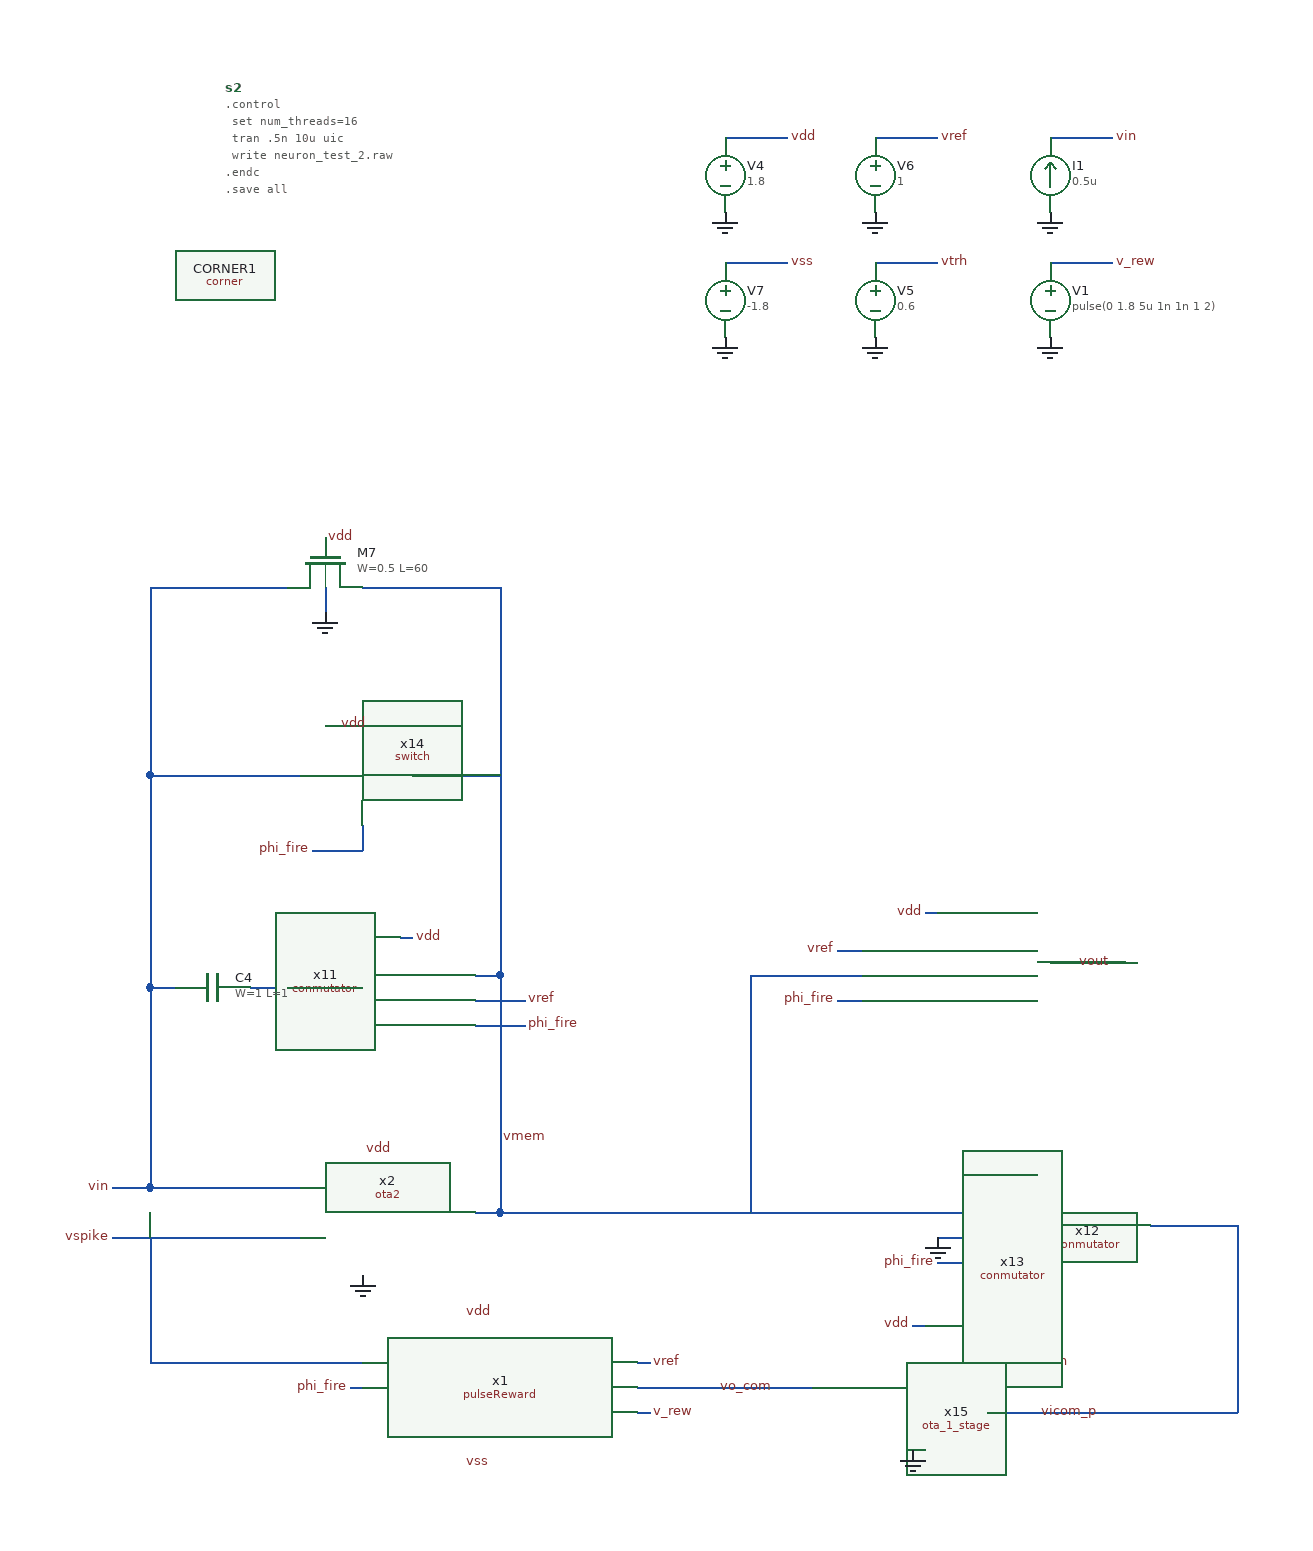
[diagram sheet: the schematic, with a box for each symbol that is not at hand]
v {xschem version=3.4.5 file_version=1.2
}
G {}
K {}
V {}
S {}
E {}
B 2 560 330 1360 730 {flags=graph
y1=0
y2=1.8
ypos1=0
ypos2=2
divy=5
subdivy=1
unity=1
x1=5e-12
x2=1e-05
divx=5
subdivx=1


dataset=-1
unitx=1
logx=0
logy=0
color=12
node=vout
linewidth_mult=5}
B 2 560 -820 1360 -420 {flags=graph

y2=1.8
ypos1=0
ypos2=2
divy=5
subdivy=1
unity=1
x1=5e-12
x2=1e-05
divx=5
subdivx=1


dataset=-1
unitx=1
logx=0
logy=0
color=7
node=vmem
y1=0
linewidth_mult=5}
B 2 560 -1220 1360 -820 {flags=graph
y1=0

ypos1=0
ypos2=2
divy=5
subdivy=1
unity=1
x1=5e-12
x2=1e-05
divx=5
subdivx=1


dataset=-1
unitx=1
logx=0
logy=0
color=4
node=vspike
y2=1.8
linewidth_mult=5}
B 2 560 -70 1360 330 {flags=graph
y1=0
y2=1.8
ypos1=0
ypos2=2
divy=5
subdivy=1
unity=1
x1=5e-12
x2=1e-05
divx=5
subdivx=1


dataset=-1
unitx=1
logx=0
logy=0

color=10
node=vin
linewidth_mult=5}
B 2 -1280 -520 -480 -120 {flags=graph
y1=-0.056
y2=1.5
ypos1=0
ypos2=2
divy=5
subdivy=1
unity=1
x1=5e-12
x2=1e-05
divx=5
subdivx=1


dataset=-1
unitx=1
logx=0
logy=0


color="4 5"
node="vicom_p
vtrh"
linewidth_mult=5}
B 2 -1330 20 -530 420 {flags=graph
y1=4.9e-05
y2=1.9
ypos1=0
ypos2=2
divy=5
subdivy=1
unity=1
x1=5e-12
x2=1e-05
divx=5
subdivx=1


dataset=-1
unitx=1
logx=0
logy=0



color=6
node=vo_com
linewidth_mult=5}
B 2 -1330 420 -530 820 {flags=graph
y1=-0.096
y2=1.9
ypos1=0
ypos2=2
divy=5
subdivy=1
unity=1
x1=5e-12
x2=1e-05
divx=5
subdivx=1


dataset=-1
unitx=1
logx=0
logy=0




color=8
node=phi_fire
linewidth_mult=5}
B 2 -1280 -920 -480 -520 {flags=graph
y1=0
y2=1.8
ypos1=0
ypos2=2
divy=5
subdivy=1
unity=1
x1=5e-12
x2=1e-05
divx=5
subdivx=1


dataset=-1
unitx=1
logx=0
logy=0


color=12
node=v_rew
linewidth_mult=5}
B 2 1360 -820 2160 -420 {flags=graph
y1=0
y2=1.8
ypos1=0
ypos2=2
divy=5
subdivy=1
unity=1
x1=5e-12
x2=1e-05
divx=5
subdivx=1


dataset=-1
unitx=1
logx=0
logy=0
color=12
node=vout
linewidth_mult=5}
B 2 1360 -1220 2160 -820 {flags=graph
y1=0
y2=1.8
ypos1=0
ypos2=2
divy=5
subdivy=1
unity=1
x1=5e-12
x2=1e-05
divx=5
subdivx=1


dataset=-1
unitx=1
logx=0
logy=0

color=10
node=vin
linewidth_mult=5}
B 2 -2130 420 -1330 820 {flags=graph
y1=-0.056
y2=1.5
ypos1=0
ypos2=2
divy=5
subdivy=1
unity=1
x1=5e-12
x2=1e-05
divx=5
subdivx=1


dataset=-1
unitx=1
logx=0
logy=0


color="4 5"
node="vicom_p
vtrh"
linewidth_mult=5}
B 2 -2130 20 -1330 420 {flags=graph
y1=0
y2=1.8
ypos1=0
ypos2=2
divy=5
subdivy=1
unity=1
x1=5e-12
x2=1e-05
divx=5
subdivx=1


dataset=-1
unitx=1
logx=0
logy=0


color=12
node=v_rew
linewidth_mult=5}
N 140 620 170 620 {
lab=vo_com}
N 310 600 350 600 {
lab=vtrh}
N 250 570 260 570 {
lab=vdd}
N 190 310 210 310 {
lab=phi_fire}
N 190 270 210 270 {
lab=vref}
N 360 280 380 280 {
lab=vout}
N -160 260 -150 260 {
lab=vdd}
N -100 310 -60 310 {
lab=vref}
N -100 290 -80 290 {
lab=vmem}
N -100 330 -60 330 {
lab=phi_fire}
N -280 300 -250 300 {
lab=#net1}
N -80 20 -80 290 {
lab=vmem}
N -360 130 -360 300 {
lab=vin}
N -360 300 -340 300 {
lab=vin}
N -360 20 -360 130 {
lab=vin}
N -190 170 -190 190 {
lab=phi_fire}
N -230 190 -190 190 {
lab=phi_fire}
N -80 290 -80 480 {
lab=vmem}
N -360 300 -360 460 {
lab=vin}
N -360 460 -240 460 {
lab=vin}
N -390 460 -360 460 {
lab=vin}
N 100 -380 150 -380 {
lab=vdd}
N 360 -380 410 -380 {
lab=vin}
N 220 -280 270 -280 {
lab=vtrh}
N 220 -380 270 -380 {
lab=vref}
N 310 640 510 640 {
lab=vicom_p}
N 270 500 290 500 {
lab=GND}
N 270 520 290 520 {
lab=phi_fire}
N 270 480 290 480 {
lab=vmem}
N 340 450 350 450 {
lab=vdd}
N 90 480 270 480 {
lab=vmem}
N 440 490 510 490 {
lab=vicom_p}
N 510 490 510 640 {
lab=vicom_p}
N -150 130 -80 130 {
lab=vmem}
N -360 130 -240 130 {
lab=vin}
N -220 90 -210 90 {
lab=vdd}
N 380 280 420 280 {
lab=vout}
N -100 480 -80 480 {
lab=vmem}
N 120 290 120 480 {
lab=vmem}
N 120 290 210 290 {
lab=vmem}
N -80 480 90 480 {
lab=vmem}
N 260 240 270 240 {
lab=vdd}
N 100 -280 150 -280 {
lab=vss}
N 250 670 260 670 {
lab=GND}
N -390 500 -240 500 {
lab=vspike}
N -360 500 -360 600 {
lab=vspike}
N -360 600 -190 600 {
lab=vspike}
N 30 620 140 620 {
lab=vo_com}
N 30 600 40 600 {
lab=vref}
N -200 620 -190 620 {
lab=phi_fire}
N -220 -20 -220 0 {
lab=GND}
N -360 -20 -250 -20 {
lab=vin}
N -360 -20 -360 20 {
lab=vin}
N -190 -20 -80 -20 {
lab=vmem}
N -80 -20 -80 20 {
lab=vmem}
N 360 -280 410 -280 {
lab=v_rew}
N 30 640 40 640 {
lab=v_rew}
C {devices/code_shown.sym} -300 -420 0 0 {name=s2 only_toplevel=false value="
.control
 set num_threads=16
 tran .5n 10u uic
 write neuron_test_2.raw
.endc
.save all" }
C {sky130_fd_pr/corner.sym} -300 -270 0 0 {name=CORNER1 only_toplevel=true corner=tt}
C {devices/lab_wire.sym} -110 560 0 1 {name=p48 sig_type=std_logic lab=vdd}
C {devices/lab_wire.sym} 140 620 0 0 {name=p49 sig_type=std_logic lab=vo_com}
C {devices/lab_wire.sym} 350 600 0 1 {name=p50 sig_type=std_logic lab=vtrh}
C {devices/lab_wire.sym} 250 570 0 0 {name=p51 sig_type=std_logic lab=vdd}
C {devices/lab_wire.sym} -390 500 0 0 {name=p52 sig_type=std_logic lab=vspike}
C {devices/lab_wire.sym} 190 310 0 0 {name=p53 sig_type=std_logic lab=phi_fire}
C {devices/lab_wire.sym} 190 270 0 0 {name=p54 sig_type=std_logic lab=vref}
C {devices/lab_wire.sym} 260 240 0 0 {name=p56 sig_type=std_logic lab=vdd}
C {devices/lab_wire.sym} -150 260 0 1 {name=p57 sig_type=std_logic lab=vdd}
C {devices/lab_wire.sym} -60 330 0 1 {name=p58 sig_type=std_logic lab=phi_fire}
C {devices/lab_wire.sym} -230 190 0 0 {name=p59 sig_type=std_logic lab=phi_fire}
C {devices/lab_wire.sym} -80 420 0 1 {name=p60 sig_type=std_logic lab=vmem}
C {devices/gnd.sym} 360 -320 0 0 {name=l8 lab=GND}
C {devices/vsource.sym} 100 -350 0 0 {name=V4 value=1.8}
C {devices/gnd.sym} 100 -320 0 0 {name=l9 lab=GND}
C {devices/lab_wire.sym} 150 -380 0 1 {name=p61 sig_type=std_logic lab=vdd}
C {devices/lab_wire.sym} 410 -380 0 1 {name=p62 sig_type=std_logic lab=vin}
C {devices/vsource.sym} 220 -250 0 0 {name=V5 value=0.6}
C {devices/gnd.sym} 220 -220 0 0 {name=l10 lab=GND}
C {devices/lab_wire.sym} 270 -280 0 1 {name=p63 sig_type=std_logic lab=vtrh}
C {devices/vsource.sym} 220 -350 0 0 {name=V6 value=1}
C {devices/gnd.sym} 220 -320 0 0 {name=l11 lab=GND}
C {devices/lab_wire.sym} 270 -380 0 1 {name=p64 sig_type=std_logic lab=vref}
C {devices/lab_wire.sym} -390 460 0 0 {name=p65 sig_type=std_logic lab=vin}
C {devices/isource.sym} 360 -350 2 1 {name=I1 value=0.5u}
C {devices/lab_wire.sym} 350 640 2 0 {name=p66 sig_type=std_logic lab=vicom_p}
C {/home/user/Documentos/conmutator.sym} -100 360 0 1 {name=x11}
C {/home/user/Documentos/conmutator.sym} 210 340 0 0 {name=x12}
C {devices/lab_wire.sym} 270 520 0 0 {name=p67 sig_type=std_logic lab=phi_fire}
C {devices/lab_wire.sym} 340 450 0 0 {name=p68 sig_type=std_logic lab=vdd}
C {/home/user/Documentos/conmutator.sym} 290 550 0 0 {name=x13}
C {devices/gnd.sym} 270 500 1 1 {name=l12 lab=GND}
C {/home/user/Documentos/switch.sym} -260 190 0 0 {name=x14}
C {devices/lab_wire.sym} -210 90 0 1 {name=p69 sig_type=std_logic lab=vdd}
C {devices/lab_wire.sym} 410 280 0 0 {name=p70 sig_type=std_logic lab=vout}
C {devices/lab_wire.sym} -60 310 0 1 {name=p71 sig_type=std_logic lab=vref}
C {/home/user/Documentos/ota_1_stage.sym} 260 620 0 1 {name=x15}
C {devices/vsource.sym} 100 -250 0 0 {name=V7 value=-1.8}
C {devices/gnd.sym} 100 -220 0 0 {name=l13 lab=GND}
C {devices/lab_wire.sym} 150 -280 0 1 {name=p72 sig_type=std_logic lab=vss}
C {devices/gnd.sym} 250 670 0 1 {name=l14 lab=GND}
C {devices/lab_wire.sym} 40 600 0 1 {name=p1 sig_type=std_logic lab=vref}
C {devices/lab_wire.sym} -200 620 2 1 {name=p2 sig_type=std_logic lab=phi_fire}
C {sky130_fd_pr/cap_mim_m3_2.sym} -310 300 3 0 {name=C4 model=cap_mim_m3_2 W=1 L=1 MF=200 spiceprefix=X}
C {sky130_fd_pr/nfet_01v8.sym} -220 -40 1 0 {name=M7
L=60
W=0.5
nf=1 mult=1
model=nfet_01v8
spiceprefix=X
}
C {devices/gnd.sym} -220 0 0 0 {name=l17 lab=GND}
C {devices/lab_wire.sym} -110 680 0 1 {name=p3 sig_type=std_logic lab=vss}
C {devices/lab_wire.sym} -220 -60 0 1 {name=p4 sig_type=std_logic lab=vdd}
C {/home/user/Documentos/pulseReward.sym} -80 610 0 1 {name=x1}
C {devices/vsource.sym} 360 -250 0 0 {name=V1 value="pulse(0 1.8 5u 1n 1n 1 2)"}
C {devices/gnd.sym} 360 -220 0 0 {name=l2 lab=GND}
C {devices/lab_wire.sym} 410 -280 0 1 {name=p5 sig_type=std_logic lab=v_rew}
C {devices/lab_wire.sym} 40 640 0 1 {name=p6 sig_type=std_logic lab=v_rew}
C {/home/user/Documentos/ota2.sym} -190 480 0 0 {name=x2}
C {devices/gnd.sym} -190 530 0 1 {name=l1 lab=GND}
C {devices/lab_wire.sym} -190 430 0 1 {name=p7 sig_type=std_logic lab=vdd}
